VERSION 5.7 ;
  NAMESCASESENSITIVE ON ;
  NOWIREEXTENSIONATPIN ON ;
  DIVIDERCHAR "/" ;
  BUSBITCHARS "[]" ;
UNITS
  DATABASE MICRONS 200 ;
END UNITS

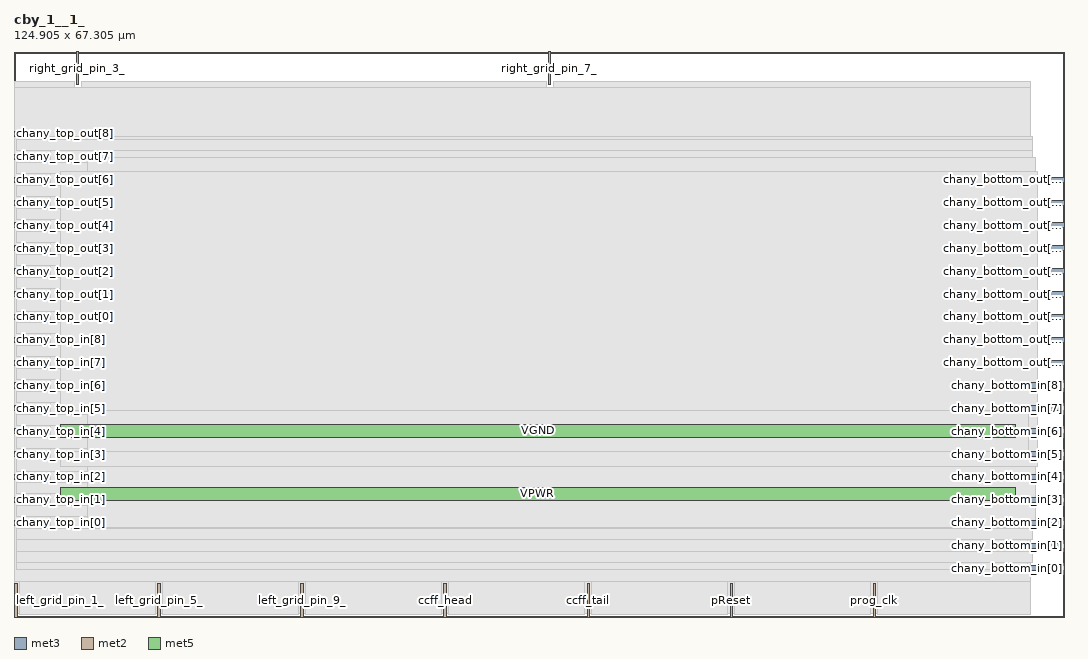
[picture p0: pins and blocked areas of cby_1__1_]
MACRO cby_1__1_
  CLASS BLOCK ;
  FOREIGN cby_1__1_ ;
  ORIGIN 0.000 0.000 ;
  SIZE 124.905 BY 67.305 ;
  PIN chany_top_in[0]
    DIRECTION INPUT ;
    PORT
      LAYER met3 ;
        RECT 0.000 10.920 4.000 11.520 ;
    END
  END chany_top_in[0]
  PIN chany_top_in[1]
    DIRECTION INPUT ;
    PORT
      LAYER met3 ;
        RECT 0.000 13.640 4.000 14.240 ;
    END
  END chany_top_in[1]
  PIN chany_top_in[2]
    DIRECTION INPUT ;
    PORT
      LAYER met3 ;
        RECT 0.000 16.360 4.000 16.960 ;
    END
  END chany_top_in[2]
  PIN chany_top_in[3]
    DIRECTION INPUT ;
    PORT
      LAYER met3 ;
        RECT 0.000 19.080 4.000 19.680 ;
    END
  END chany_top_in[3]
  PIN chany_top_in[4]
    DIRECTION INPUT ;
    PORT
      LAYER met3 ;
        RECT 0.000 21.800 4.000 22.400 ;
    END
  END chany_top_in[4]
  PIN chany_top_in[5]
    DIRECTION INPUT ;
    PORT
      LAYER met3 ;
        RECT 0.000 24.520 4.000 25.120 ;
    END
  END chany_top_in[5]
  PIN chany_top_in[6]
    DIRECTION INPUT ;
    PORT
      LAYER met3 ;
        RECT 0.000 27.240 4.000 27.840 ;
    END
  END chany_top_in[6]
  PIN chany_top_in[7]
    DIRECTION INPUT ;
    PORT
      LAYER met3 ;
        RECT 0.000 29.960 4.000 30.560 ;
    END
  END chany_top_in[7]
  PIN chany_top_in[8]
    DIRECTION INPUT ;
    PORT
      LAYER met3 ;
        RECT 0.000 32.680 4.000 33.280 ;
    END
  END chany_top_in[8]
  PIN chany_top_out[0]
    DIRECTION OUTPUT TRISTATE ;
    PORT
      LAYER met3 ;
        RECT 0.000 35.400 4.000 36.000 ;
    END
  END chany_top_out[0]
  PIN chany_top_out[1]
    DIRECTION OUTPUT TRISTATE ;
    PORT
      LAYER met3 ;
        RECT 0.000 38.120 4.000 38.720 ;
    END
  END chany_top_out[1]
  PIN chany_top_out[2]
    DIRECTION OUTPUT TRISTATE ;
    PORT
      LAYER met3 ;
        RECT 0.000 40.840 4.000 41.440 ;
    END
  END chany_top_out[2]
  PIN chany_top_out[3]
    DIRECTION OUTPUT TRISTATE ;
    PORT
      LAYER met3 ;
        RECT 0.000 43.560 4.000 44.160 ;
    END
  END chany_top_out[3]
  PIN chany_top_out[4]
    DIRECTION OUTPUT TRISTATE ;
    PORT
      LAYER met3 ;
        RECT 0.000 46.280 4.000 46.880 ;
    END
  END chany_top_out[4]
  PIN chany_top_out[5]
    DIRECTION OUTPUT TRISTATE ;
    PORT
      LAYER met3 ;
        RECT 0.000 49.000 4.000 49.600 ;
    END
  END chany_top_out[5]
  PIN chany_top_out[6]
    DIRECTION OUTPUT TRISTATE ;
    PORT
      LAYER met3 ;
        RECT 0.000 51.720 4.000 52.320 ;
    END
  END chany_top_out[6]
  PIN chany_top_out[7]
    DIRECTION OUTPUT TRISTATE ;
    PORT
      LAYER met3 ;
        RECT 0.000 54.440 4.000 55.040 ;
    END
  END chany_top_out[7]
  PIN chany_top_out[8]
    DIRECTION OUTPUT TRISTATE ;
    PORT
      LAYER met3 ;
        RECT 0.000 57.160 4.000 57.760 ;
    END
  END chany_top_out[8]
  PIN right_grid_pin_3_
    DIRECTION OUTPUT TRISTATE ;
    PORT
      LAYER met2 ;
        RECT 7.450 63.305 7.730 67.305 ;
    END
  END right_grid_pin_3_
  PIN right_grid_pin_7_
    DIRECTION OUTPUT TRISTATE ;
    PORT
      LAYER met2 ;
        RECT 63.570 63.305 63.850 67.305 ;
    END
  END right_grid_pin_7_
  PIN chany_bottom_in[0]
    DIRECTION INPUT ;
    PORT
      LAYER met3 ;
        RECT 120.905 5.480 124.905 6.080 ;
    END
  END chany_bottom_in[0]
  PIN chany_bottom_in[1]
    DIRECTION INPUT ;
    PORT
      LAYER met3 ;
        RECT 120.905 8.200 124.905 8.800 ;
    END
  END chany_bottom_in[1]
  PIN chany_bottom_in[2]
    DIRECTION INPUT ;
    PORT
      LAYER met3 ;
        RECT 120.905 10.920 124.905 11.520 ;
    END
  END chany_bottom_in[2]
  PIN chany_bottom_in[3]
    DIRECTION INPUT ;
    PORT
      LAYER met3 ;
        RECT 120.905 13.640 124.905 14.240 ;
    END
  END chany_bottom_in[3]
  PIN chany_bottom_in[4]
    DIRECTION INPUT ;
    PORT
      LAYER met3 ;
        RECT 120.905 16.360 124.905 16.960 ;
    END
  END chany_bottom_in[4]
  PIN chany_bottom_in[5]
    DIRECTION INPUT ;
    PORT
      LAYER met3 ;
        RECT 120.905 19.080 124.905 19.680 ;
    END
  END chany_bottom_in[5]
  PIN chany_bottom_in[6]
    DIRECTION INPUT ;
    PORT
      LAYER met3 ;
        RECT 120.905 21.800 124.905 22.400 ;
    END
  END chany_bottom_in[6]
  PIN chany_bottom_in[7]
    DIRECTION INPUT ;
    PORT
      LAYER met3 ;
        RECT 120.905 24.520 124.905 25.120 ;
    END
  END chany_bottom_in[7]
  PIN chany_bottom_in[8]
    DIRECTION INPUT ;
    PORT
      LAYER met3 ;
        RECT 120.905 27.240 124.905 27.840 ;
    END
  END chany_bottom_in[8]
  PIN chany_bottom_out[0]
    DIRECTION OUTPUT TRISTATE ;
    PORT
      LAYER met3 ;
        RECT 120.905 29.960 124.905 30.560 ;
    END
  END chany_bottom_out[0]
  PIN chany_bottom_out[1]
    DIRECTION OUTPUT TRISTATE ;
    PORT
      LAYER met3 ;
        RECT 120.905 32.680 124.905 33.280 ;
    END
  END chany_bottom_out[1]
  PIN chany_bottom_out[2]
    DIRECTION OUTPUT TRISTATE ;
    PORT
      LAYER met3 ;
        RECT 120.905 35.400 124.905 36.000 ;
    END
  END chany_bottom_out[2]
  PIN chany_bottom_out[3]
    DIRECTION OUTPUT TRISTATE ;
    PORT
      LAYER met3 ;
        RECT 120.905 38.120 124.905 38.720 ;
    END
  END chany_bottom_out[3]
  PIN chany_bottom_out[4]
    DIRECTION OUTPUT TRISTATE ;
    PORT
      LAYER met3 ;
        RECT 120.905 40.840 124.905 41.440 ;
    END
  END chany_bottom_out[4]
  PIN chany_bottom_out[5]
    DIRECTION OUTPUT TRISTATE ;
    PORT
      LAYER met3 ;
        RECT 120.905 43.560 124.905 44.160 ;
    END
  END chany_bottom_out[5]
  PIN chany_bottom_out[6]
    DIRECTION OUTPUT TRISTATE ;
    PORT
      LAYER met3 ;
        RECT 120.905 46.280 124.905 46.880 ;
    END
  END chany_bottom_out[6]
  PIN chany_bottom_out[7]
    DIRECTION OUTPUT TRISTATE ;
    PORT
      LAYER met3 ;
        RECT 120.905 49.000 124.905 49.600 ;
    END
  END chany_bottom_out[7]
  PIN chany_bottom_out[8]
    DIRECTION OUTPUT TRISTATE ;
    PORT
      LAYER met3 ;
        RECT 120.905 51.720 124.905 52.320 ;
    END
  END chany_bottom_out[8]
  PIN left_grid_pin_1_
    DIRECTION OUTPUT TRISTATE ;
    PORT
      LAYER met2 ;
        RECT 0.090 0.000 0.370 4.000 ;
    END
  END left_grid_pin_1_
  PIN left_grid_pin_5_
    DIRECTION OUTPUT TRISTATE ;
    PORT
      LAYER met2 ;
        RECT 17.110 0.000 17.390 4.000 ;
    END
  END left_grid_pin_5_
  PIN left_grid_pin_9_
    DIRECTION OUTPUT TRISTATE ;
    PORT
      LAYER met2 ;
        RECT 34.130 0.000 34.410 4.000 ;
    END
  END left_grid_pin_9_
  PIN ccff_head
    DIRECTION INPUT ;
    PORT
      LAYER met2 ;
        RECT 51.150 0.000 51.430 4.000 ;
    END
  END ccff_head
  PIN ccff_tail
    DIRECTION OUTPUT TRISTATE ;
    PORT
      LAYER met2 ;
        RECT 68.170 0.000 68.450 4.000 ;
    END
  END ccff_tail
  PIN pReset
    DIRECTION INPUT ;
    PORT
      LAYER met2 ;
        RECT 85.190 0.000 85.470 4.000 ;
    END
  END pReset
  PIN prog_clk
    DIRECTION INPUT ;
    PORT
      LAYER met2 ;
        RECT 102.210 0.000 102.490 4.000 ;
    END
  END prog_clk
  PIN VPWR
    DIRECTION INPUT ;
    USE POWER ;
    PORT
      LAYER met5 ;
        RECT 5.520 13.840 119.140 15.440 ;
    END
  END VPWR
  PIN VGND
    DIRECTION INPUT ;
    USE GROUND ;
    PORT
      LAYER met5 ;
        RECT 5.520 21.340 119.140 22.940 ;
    END
  END VGND
  OBS
      LAYER li1 ;
        RECT 5.520 10.795 119.140 54.485 ;
      LAYER met1 ;
        RECT 0.070 0.380 120.910 54.640 ;
      LAYER met2 ;
        RECT 0.090 63.025 7.170 63.650 ;
        RECT 8.010 63.025 63.290 63.650 ;
        RECT 64.130 63.025 120.890 63.650 ;
        RECT 0.090 4.280 120.890 63.025 ;
        RECT 0.650 0.270 16.830 4.280 ;
        RECT 17.670 0.270 33.850 4.280 ;
        RECT 34.690 0.270 50.870 4.280 ;
        RECT 51.710 0.270 67.890 4.280 ;
        RECT 68.730 0.270 84.910 4.280 ;
        RECT 85.750 0.270 101.930 4.280 ;
        RECT 102.770 0.270 120.890 4.280 ;
      LAYER met3 ;
        RECT 4.400 56.760 121.170 57.160 ;
        RECT 0.310 55.440 121.170 56.760 ;
        RECT 4.400 54.040 121.170 55.440 ;
        RECT 0.310 52.720 121.170 54.040 ;
        RECT 4.400 51.320 120.505 52.720 ;
        RECT 0.310 50.000 121.170 51.320 ;
        RECT 4.400 48.600 120.505 50.000 ;
        RECT 0.310 47.280 121.170 48.600 ;
        RECT 4.400 45.880 120.505 47.280 ;
        RECT 0.310 44.560 121.170 45.880 ;
        RECT 4.400 43.160 120.505 44.560 ;
        RECT 0.310 41.840 121.170 43.160 ;
        RECT 4.400 40.440 120.505 41.840 ;
        RECT 0.310 39.120 121.170 40.440 ;
        RECT 4.400 37.720 120.505 39.120 ;
        RECT 0.310 36.400 121.170 37.720 ;
        RECT 4.400 35.000 120.505 36.400 ;
        RECT 0.310 33.680 121.170 35.000 ;
        RECT 4.400 32.280 120.505 33.680 ;
        RECT 0.310 30.960 121.170 32.280 ;
        RECT 4.400 29.560 120.505 30.960 ;
        RECT 0.310 28.240 121.170 29.560 ;
        RECT 4.400 26.840 120.505 28.240 ;
        RECT 0.310 25.520 121.170 26.840 ;
        RECT 4.400 24.120 120.505 25.520 ;
        RECT 0.310 22.800 121.170 24.120 ;
        RECT 4.400 21.400 120.505 22.800 ;
        RECT 0.310 20.080 121.170 21.400 ;
        RECT 4.400 18.680 120.505 20.080 ;
        RECT 0.310 17.360 121.170 18.680 ;
        RECT 4.400 15.960 120.505 17.360 ;
        RECT 0.310 14.640 121.170 15.960 ;
        RECT 4.400 13.240 120.505 14.640 ;
        RECT 0.310 11.920 121.170 13.240 ;
        RECT 4.400 10.520 120.505 11.920 ;
        RECT 0.310 9.200 121.170 10.520 ;
        RECT 0.310 7.800 120.505 9.200 ;
        RECT 0.310 6.480 121.170 7.800 ;
        RECT 0.310 5.615 120.505 6.480 ;
      LAYER met4 ;
        RECT 8.720 10.640 121.570 54.640 ;
      LAYER met5 ;
        RECT 5.520 24.540 121.780 52.940 ;
        RECT 120.740 19.740 121.780 24.540 ;
        RECT 5.520 17.900 121.780 19.740 ;
  END
END cby_1__1_
END LIBRARY

